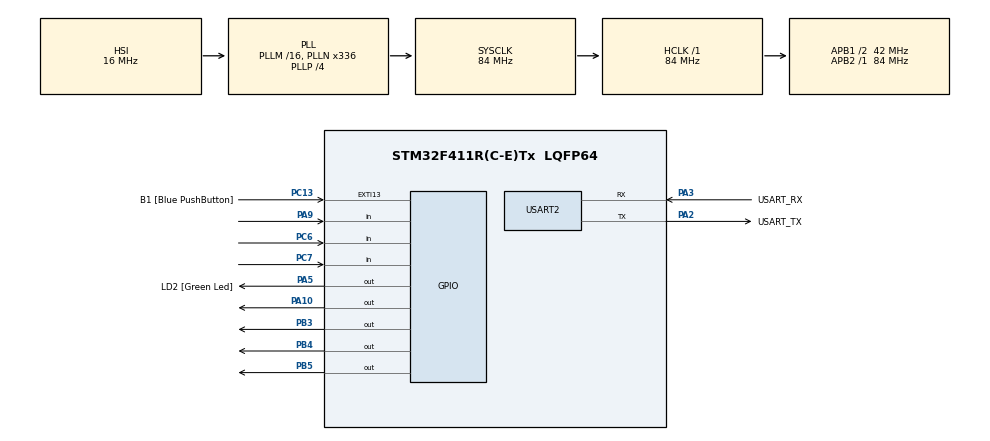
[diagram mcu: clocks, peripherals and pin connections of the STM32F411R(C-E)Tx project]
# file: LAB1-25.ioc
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Mcu.Family=STM32F4
Mcu.Name=STM32F411R(C-E)Tx
Mcu.Package=LQFP64
NVIC.PriorityGroup=NVIC_PRIORITYGROUP_0
PA10.Signal=GPIO_Output
PA13.GPIO_Label=TMS
PA13.Mode=Serial_Wire
PA13.Signal=SYS_JTMS-SWDIO
PA14.GPIO_Label=TCK
PA14.Mode=Serial_Wire
PA14.Signal=SYS_JTCK-SWCLK
PA2.GPIO_Label=USART_TX
PA2.Mode=Asynchronous
PA2.Signal=USART2_TX
PA3.GPIO_Label=USART_RX
PA3.Mode=Asynchronous
PA3.Signal=USART2_RX
PA5.GPIO_Label=LD2 [Green Led]
PA5.Signal=GPIO_Output
PA9.Signal=GPIO_Input
PB3.Signal=GPIO_Output
PB4.Signal=GPIO_Output
PB5.Signal=GPIO_Output
PC13-ANTI_TAMP.GPIO_Label=B1 [Blue PushButton]
PC13-ANTI_TAMP.GPIO_ModeDefaultEXTI=GPIO_MODE_IT_FALLING
PC13-ANTI_TAMP.Signal=GPXTI13
PC14-OSC32_IN.Mode=LSE-External-Oscillator
PC14-OSC32_IN.Signal=RCC_OSC32_IN
PC15-OSC32_OUT.Mode=LSE-External-Oscillator
PC15-OSC32_OUT.Signal=RCC_OSC32_OUT
PC6.Signal=GPIO_Input
PC7.Signal=GPIO_Input
PH0\ -\ OSC_IN.Mode=HSE-External-Clock-Source
PH0\ -\ OSC_IN.Signal=RCC_OSC_IN
PH1\ -\ OSC_OUT.Mode=HSE-External-Clock-Source
PH1\ -\ OSC_OUT.Signal=RCC_OSC_OUT
ProjectManager.HeapSize=0x200
ProjectManager.StackSize=0x400
ProjectManager.TargetToolchain=STM32CubeIDE
RCC.48MHZClocksFreq_Value=84000000
RCC.AHBFreq_Value=84000000
RCC.APB1CLKDivider=RCC_HCLK_DIV2
RCC.APB1Freq_Value=42000000
RCC.APB1TimFreq_Value=84000000
RCC.APB2Freq_Value=84000000
RCC.APB2TimFreq_Value=84000000
RCC.CortexFreq_Value=84000000
RCC.FLatency-AdvancedSettings=FLASH_LATENCY_2
RCC.HCLKFreq_Value=84000000
RCC.HSE_VALUE=8000000
RCC.HSI_VALUE=16000000
RCC.PLLN=336
RCC.PLLP=RCC_PLLP_DIV4
RCC.SYSCLKFreq_VALUE=84000000
RCC.SYSCLKSource=RCC_SYSCLKSOURCE_PLLCLK
RCC.VCOOutputFreq_Value=336000000
USART2.VirtualMode=VM_ASYNC
board=NUCLEO-F411RE

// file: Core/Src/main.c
/* USER CODE BEGIN Header */
/**
  ******************************************************************************
  * @file           : main.c
  * @brief          : Main program body
  ******************************************************************************
  * @attention
  *
  * Copyright (c) 2023 STMicroelectronics.
  * All rights reserved.
  *
  * This software is licensed under terms that can be found in the LICENSE file
  * in the root directory of this software component.
  * If no LICENSE file comes with this software, it is provided AS-IS.
  *
  ******************************************************************************
  */
/* USER CODE END Header */
#include "main.h"

UART_HandleTypeDef huart2;

/* USER CODE BEGIN PV */
struct PortPin
{
 GPIO_TypeDef* PORT;
 uint16_t PIN;
};
struct PortPin R[4] =
{
 {GPIOA,GPIO_PIN_10},
 {GPIOB,GPIO_PIN_3},
 {GPIOB,GPIO_PIN_5},
 {GPIOB,GPIO_PIN_4}
};
struct PortPin L[4] =
{
 {GPIOA,GPIO_PIN_9},
 {GPIOC,GPIO_PIN_7},
 {GPIOB,GPIO_PIN_6},
 {GPIOA,GPIO_PIN_7}
};

uint16_t ButtonMatrix = 0;
uint16_t MatrixBackup[11] = {0};
uint16_t MatrixCorrect[11] = {0b1000000000, 0b10, 0b10000000000, 0b10, 0b1000, 0b100000, 0b1000, 0b1000, 0b1000, 0b1000000, 0b100000};
uint16_t buttonLog = 0;
uint8_t flag = 0;
uint8_t checker = 0;
uint8_t k=0;
/* USER CODE END PV */

void SystemClock_Config(void);
static void MX_GPIO_Init(void);
static void MX_USART2_UART_Init(void);
void ReadMatrixButton1Row();
/* USER CODE BEGIN PFP */
//	void myState();
	void ReadMatrixButton1Row();
/* USER CODE END PFP */

int main(void)
{

  /* MCU Configuration--------------------------------------------------------*/

  /* Reset of all peripherals, Initializes the Flash interface and the Systick. */
  HAL_Init();

  /* Configure the system clock */
  SystemClock_Config();

  /* Initialize all configured peripherals */
  MX_GPIO_Init();
  MX_USART2_UART_Init();

  /* Infinite loop */
  while (1)
  {

    /* USER CODE BEGIN 3 */

	  static uint32_t timestamp = 0;
	  if(HAL_GetTick() >= timestamp)
	      {
	          timestamp = HAL_GetTick() + 100;
	          for (int j = 0; j < 4; j++) {
	              ReadMatrixButton1Row();
	              if (buttonLog == 0 && ButtonMatrix != 0 && k <= 10){ //detect switch was pressed
	                  MatrixBackup[k] = ButtonMatrix;
	                  k++;
	                 }
	                 buttonLog = ButtonMatrix; //update log status
	          }
	      }
	  if (ButtonMatrix == 0b1000000000000000){ // check from right value and input
		  for (int j=0; j<11; j++) {
			  if (MatrixBackup[j] == MatrixCorrect[j]) {
				  checker++;
			  }
		  }
	  }
	  if (checker == 11){
			  HAL_GPIO_WritePin(GPIOA, GPIO_PIN_5, GPIO_PIN_SET); //1
	  }

  if (ButtonMatrix == 0b1000000000000){ //clear
	  	  for (int j=0; j<11; j++) {
			  MatrixBackup[j] = 0;
		  }
	  	  k = 0;
	  	  HAL_GPIO_WritePin(GPIOA, GPIO_PIN_5, GPIO_PIN_RESET);
	  }
  }

  /* USER CODE END 3 */
}

void SystemClock_Config(void)
{
  RCC_OscInitTypeDef RCC_OscInitStruct = {0};
  RCC_ClkInitTypeDef RCC_ClkInitStruct = {0};

  /** Configure the main internal regulator output voltage
  */
  __HAL_RCC_PWR_CLK_ENABLE();
  __HAL_PWR_VOLTAGESCALING_CONFIG(PWR_REGULATOR_VOLTAGE_SCALE1);

  /** Initializes the RCC Oscillators according to the specified parameters
  * in the RCC_OscInitTypeDef structure.
  */
  RCC_OscInitStruct.OscillatorType = RCC_OSCILLATORTYPE_HSI;
  RCC_OscInitStruct.HSIState = RCC_HSI_ON;
  RCC_OscInitStruct.HSICalibrationValue = RCC_HSICALIBRATION_DEFAULT;
  RCC_OscInitStruct.PLL.PLLState = RCC_PLL_ON;
  RCC_OscInitStruct.PLL.PLLSource = RCC_PLLSOURCE_HSI;
  RCC_OscInitStruct.PLL.PLLM = 16;
  RCC_OscInitStruct.PLL.PLLN = 336;
  RCC_OscInitStruct.PLL.PLLP = RCC_PLLP_DIV4;
  RCC_OscInitStruct.PLL.PLLQ = 4;
  if (HAL_RCC_OscConfig(&RCC_OscInitStruct) != HAL_OK)
  {
    Error_Handler();
  }

  /** Initializes the CPU, AHB and APB buses clocks
  */
  RCC_ClkInitStruct.ClockType = RCC_CLOCKTYPE_HCLK|RCC_CLOCKTYPE_SYSCLK
                              |RCC_CLOCKTYPE_PCLK1|RCC_CLOCKTYPE_PCLK2;
  RCC_ClkInitStruct.SYSCLKSource = RCC_SYSCLKSOURCE_PLLCLK;
  RCC_ClkInitStruct.AHBCLKDivider = RCC_SYSCLK_DIV1;
  RCC_ClkInitStruct.APB1CLKDivider = RCC_HCLK_DIV2;
  RCC_ClkInitStruct.APB2CLKDivider = RCC_HCLK_DIV1;

  if (HAL_RCC_ClockConfig(&RCC_ClkInitStruct, FLASH_LATENCY_2) != HAL_OK)
  {
    Error_Handler();
  }
}

static void MX_USART2_UART_Init(void)
{

  huart2.Instance = USART2;
  huart2.Init.BaudRate = 115200;
  huart2.Init.WordLength = UART_WORDLENGTH_8B;
  huart2.Init.StopBits = UART_STOPBITS_1;
  huart2.Init.Parity = UART_PARITY_NONE;
  huart2.Init.Mode = UART_MODE_TX_RX;
  huart2.Init.HwFlowCtl = UART_HWCONTROL_NONE;
  huart2.Init.OverSampling = UART_OVERSAMPLING_16;
  if (HAL_UART_Init(&huart2) != HAL_OK)
  {
    Error_Handler();
  }

}

static void MX_GPIO_Init(void)
{
  GPIO_InitTypeDef GPIO_InitStruct = {0};

  /* GPIO Ports Clock Enable */
  __HAL_RCC_GPIOC_CLK_ENABLE();
  __HAL_RCC_GPIOH_CLK_ENABLE();
  __HAL_RCC_GPIOA_CLK_ENABLE();
  __HAL_RCC_GPIOB_CLK_ENABLE();

  /*Configure GPIO pin Output Level */
  HAL_GPIO_WritePin(LD2_GPIO_Port, LD2_Pin, GPIO_PIN_RESET);

  /*Configure GPIO pin Output Level */
  HAL_GPIO_WritePin(GPIOA, GPIO_PIN_10, GPIO_PIN_SET);

  /*Configure GPIO pin Output Level */
  HAL_GPIO_WritePin(GPIOB, GPIO_PIN_3|GPIO_PIN_4|GPIO_PIN_5, GPIO_PIN_SET);

  /*Configure GPIO pin : B1_Pin */
  GPIO_InitStruct.Pin = B1_Pin;
  GPIO_InitStruct.Mode = GPIO_MODE_IT_FALLING;
  GPIO_InitStruct.Pull = GPIO_NOPULL;
  HAL_GPIO_Init(B1_GPIO_Port, &GPIO_InitStruct);

  /*Configure GPIO pin : LD2_Pin */
  GPIO_InitStruct.Pin = LD2_Pin;
  GPIO_InitStruct.Mode = GPIO_MODE_OUTPUT_PP;
  GPIO_InitStruct.Pull = GPIO_NOPULL;
  GPIO_InitStruct.Speed = GPIO_SPEED_FREQ_LOW;
  HAL_GPIO_Init(LD2_GPIO_Port, &GPIO_InitStruct);

  /*Configure GPIO pins : PA7 PA9 */
  GPIO_InitStruct.Pin = GPIO_PIN_7|GPIO_PIN_9;
  GPIO_InitStruct.Mode = GPIO_MODE_INPUT;
  GPIO_InitStruct.Pull = GPIO_PULLUP;
  HAL_GPIO_Init(GPIOA, &GPIO_InitStruct);

  /*Configure GPIO pin : PC7 */
  GPIO_InitStruct.Pin = GPIO_PIN_7;
  GPIO_InitStruct.Mode = GPIO_MODE_INPUT;
  GPIO_InitStruct.Pull = GPIO_PULLUP;
  HAL_GPIO_Init(GPIOC, &GPIO_InitStruct);

  /*Configure GPIO pin : PA10 */
  GPIO_InitStruct.Pin = GPIO_PIN_10;
  GPIO_InitStruct.Mode = GPIO_MODE_OUTPUT_OD;
  GPIO_InitStruct.Pull = GPIO_NOPULL;
  GPIO_InitStruct.Speed = GPIO_SPEED_FREQ_LOW;
  HAL_GPIO_Init(GPIOA, &GPIO_InitStruct);

  /*Configure GPIO pins : PB3 PB4 PB5 */
  GPIO_InitStruct.Pin = GPIO_PIN_3|GPIO_PIN_4|GPIO_PIN_5;
  GPIO_InitStruct.Mode = GPIO_MODE_OUTPUT_OD;
  GPIO_InitStruct.Pull = GPIO_NOPULL;
  GPIO_InitStruct.Speed = GPIO_SPEED_FREQ_LOW;
  HAL_GPIO_Init(GPIOB, &GPIO_InitStruct);

  /*Configure GPIO pin : PB6 */
  GPIO_InitStruct.Pin = GPIO_PIN_6;
  GPIO_InitStruct.Mode = GPIO_MODE_INPUT;
  GPIO_InitStruct.Pull = GPIO_PULLUP;
  HAL_GPIO_Init(GPIOB, &GPIO_InitStruct);

}

/* USER CODE BEGIN 4 */
void ReadMatrixButton1Row()
{
 static uint8_t X = 0;
 register int i;
 for (i = 0; i < 4; i++) //for reading L each position
 {
  if(HAL_GPIO_ReadPin(L[i].PORT, L[i].PIN) == 1) //true -> high
  {
   ButtonMatrix &= ~(1<<(X*4 + i));
  }
  else if (HAL_GPIO_ReadPin(L[i].PORT, L[i].PIN) == 0 ) //false -> low
  {
   ButtonMatrix |= 1<<(X*4+i);
  }
 }
 // SET RX
 HAL_GPIO_WritePin(R[X].PORT, R[X].PIN, 1);

 // RESET RX+1%4
 HAL_GPIO_WritePin(R[(X+1)%4].PORT, R[(X+1)%4].PIN, 0);
 X++;
 X%=4;

}

/* USER CODE END 4 */

void Error_Handler(void)
{
  __disable_irq();
  while (1)
  {
  }
}
